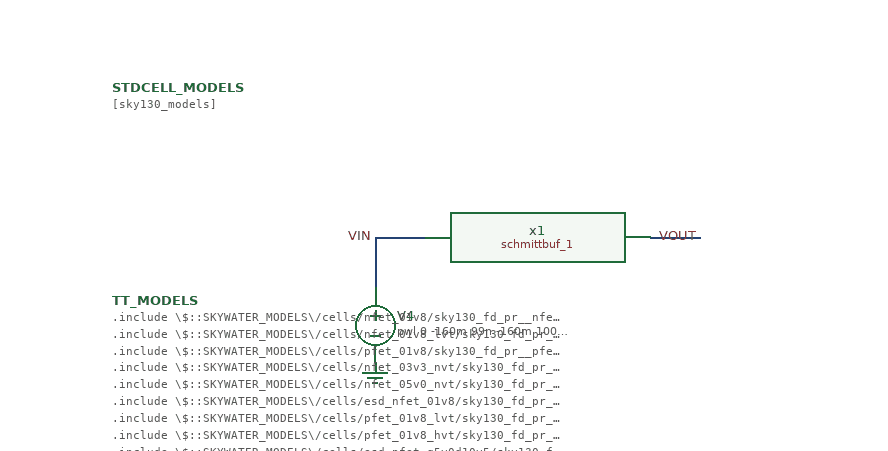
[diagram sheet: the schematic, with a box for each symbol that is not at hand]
v {xschem version=2.9.9 file_version=1.2 }
G {}
K {}
V {}
S {}
E {}
N 100 50 140 50 { lab=VOUT}
N -120 50 -80 50 { lab=VIN}
N -120 50 -120 90 { lab=VIN}
C {sky130_stdcells/schmittbuf_1.sym} -60 80 0 0 {name=x1 VGND=VGND VNB=VNB VPB=VPB VPWR=VPWR prefix=sky130_fd_sc_hvl__ }
C {devices/vsource.sym} -120 120 0 0 {name=V4 value="pwl 0 -160m 99n -160m 100n -140m 199n -140m 200n -120m 299n -120m 300n -100m 399n -100m 400n -80m 499n -80m 500n -60m 599n -60m 600n -40m 699n -40m 700n -20m 799n -20m 800n 0 899n 0 900n 20m 999n 20m 1u 40m 1.099u 40m 1.1u 60m 1.199u 60m 1.2u 80m 1.299u 80m 1.3u 100m 1.399u 100m 1.4u 120m 1.499u 120m 1.5u 140m 1.599u 140m 1.6u 160m 1.699u 160m"}
C {devices/gnd.sym} -120 150 0 0 {name=l1 lab=GND}
C {devices/lab_wire.sym} -120 50 0 0 {name=l2 sig_type=std_logic lab=VIN}
C {devices/lab_wire.sym} 140 50 0 0 {name=l3 sig_type=std_logic lab=VOUT}
C {devices/code.sym} -330 -70 0 0 {name=STDCELL_MODELS 
only_toplevel=true
place=end
format="tcleval(@value )"
value="[sky130_models]"
name=s1 only_toplevel=false value=blabla}
C {devices/code.sym} -330 100 0 0 {name=TT_MODELS
only_toplevel=true
format="tcleval( @value )"
value="
.include \\\\$::SKYWATER_MODELS\\\\/cells/nfet_01v8/sky130_fd_pr__nfet_01v8__tt.corner.spice
.include \\\\$::SKYWATER_MODELS\\\\/cells/nfet_01v8_lvt/sky130_fd_pr__nfet_01v8_lvt__tt.corner.spice
.include \\\\$::SKYWATER_MODELS\\\\/cells/pfet_01v8/sky130_fd_pr__pfet_01v8__tt.corner.spice
.include \\\\$::SKYWATER_MODELS\\\\/cells/nfet_03v3_nvt/sky130_fd_pr__nfet_03v3_nvt__tt.corner.spice
.include \\\\$::SKYWATER_MODELS\\\\/cells/nfet_05v0_nvt/sky130_fd_pr__nfet_05v0_nvt__tt.corner.spice
.include \\\\$::SKYWATER_MODELS\\\\/cells/esd_nfet_01v8/sky130_fd_pr__esd_nfet_01v8__tt.corner.spice
.include \\\\$::SKYWATER_MODELS\\\\/cells/pfet_01v8_lvt/sky130_fd_pr__pfet_01v8_lvt__tt.corner.spice
.include \\\\$::SKYWATER_MODELS\\\\/cells/pfet_01v8_hvt/sky130_fd_pr__pfet_01v8_hvt__tt.corner.spice
.include \\\\$::SKYWATER_MODELS\\\\/cells/esd_pfet_g5v0d10v5/sky130_fd_pr__esd_pfet_g5v0d10v5__tt.corner.spice
.include \\\\$::SKYWATER_MODELS\\\\/cells/pfet_g5v0d10v5/sky130_fd_pr__pfet_g5v0d10v5__tt.corner.spice
.include \\\\$::SKYWATER_MODELS\\\\/cells/pfet_g5v0d16v0/sky130_fd_pr__pfet_g5v0d16v0__tt.corner.spice
.include \\\\$::SKYWATER_MODELS\\\\/cells/nfet_g5v0d10v5/sky130_fd_pr__nfet_g5v0d10v5__tt.corner.spice
.include \\\\$::SKYWATER_MODELS\\\\/cells/nfet_g5v0d16v0/sky130_fd_pr__nfet_g5v0d16v0__tt_discrete.corner.spice
.include \\\\$::SKYWATER_MODELS\\\\/cells/esd_nfet_g5v0d10v5/sky130_fd_pr__esd_nfet_g5v0d10v5__tt.corner.spice
.include \\\\$::SKYWATER_MODELS\\\\/models/corners/tt/nonfet.spice
* Mismatch parameters
.include \\\\$::SKYWATER_MODELS\\\\/cells/nfet_01v8/sky130_fd_pr__nfet_01v8__mismatch.corner.spice
.include \\\\$::SKYWATER_MODELS\\\\/cells/pfet_01v8/sky130_fd_pr__pfet_01v8__mismatch.corner.spice
.include \\\\$::SKYWATER_MODELS\\\\/cells/nfet_01v8_lvt/sky130_fd_pr__nfet_01v8_lvt__mismatch.corner.spice
.include \\\\$::SKYWATER_MODELS\\\\/cells/pfet_01v8_lvt/sky130_fd_pr__pfet_01v8_lvt__mismatch.corner.spice
.include \\\\$::SKYWATER_MODELS\\\\/cells/pfet_01v8_hvt/sky130_fd_pr__pfet_01v8_hvt__mismatch.corner.spice
.include \\\\$::SKYWATER_MODELS\\\\/cells/nfet_g5v0d10v5/sky130_fd_pr__nfet_g5v0d10v5__mismatch.corner.spice
.include \\\\$::SKYWATER_MODELS\\\\/cells/pfet_g5v0d10v5/sky130_fd_pr__pfet_g5v0d10v5__mismatch.corner.spice
.include \\\\$::SKYWATER_MODELS\\\\/cells/nfet_05v0_nvt/sky130_fd_pr__nfet_05v0_nvt__mismatch.corner.spice
.include \\\\$::SKYWATER_MODELS\\\\/cells/nfet_03v3_nvt/sky130_fd_pr__nfet_03v3_nvt__mismatch.corner.spice
* Resistor\\\\$::SKYWATER_MODELS\\\\/Capacitor
.include \\\\$::SKYWATER_MODELS\\\\/models/r+c/res_typical__cap_typical.spice
.include \\\\$::SKYWATER_MODELS\\\\/models/r+c/res_typical__cap_typical__lin.spice
* Special cells
.include \\\\$::SKYWATER_MODELS\\\\/models/corners/tt/specialized_cells.spice
* All models
.include \\\\$::SKYWATER_MODELS\\\\/models/all.spice
* Corner
.include \\\\$::SKYWATER_MODELS\\\\/models/corners/tt/rf.spice
"
}
